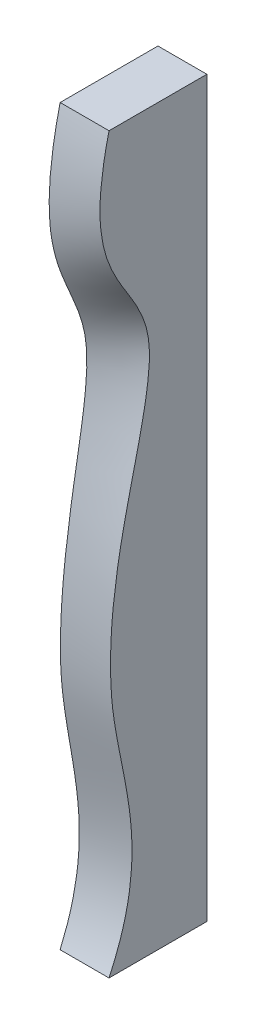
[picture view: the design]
ISO-10303-21;
HEADER;
FILE_DESCRIPTION(('STEP AP214'),'2;1');
FILE_NAME('part.step','',(''),(''),'','','');
FILE_SCHEMA(('AUTOMOTIVE_DESIGN { 1 0 10303 214 1 1 1 1 }'));
ENDSEC;
DATA;
#1=APPLICATION_CONTEXT('core data for automotive mechanical design processes');
#2=APPLICATION_PROTOCOL_DEFINITION('international standard','automotive_design',2000,#1);
#3=PRODUCT_CONTEXT('',#1,'mechanical');
#4=PRODUCT('Part','Part','',(#3));
#5=PRODUCT_RELATED_PRODUCT_CATEGORY('part','',(#4));
#6=PRODUCT_DEFINITION_FORMATION('','',#4);
#7=PRODUCT_DEFINITION_CONTEXT('part definition',#1,'design');
#8=PRODUCT_DEFINITION('design','',#6,#7);
#9=PRODUCT_DEFINITION_SHAPE('','',#8);
#10=(LENGTH_UNIT() NAMED_UNIT(*) SI_UNIT(.MILLI.,.METRE.));
#11=(NAMED_UNIT(*) PLANE_ANGLE_UNIT() SI_UNIT($,.RADIAN.));
#12=(NAMED_UNIT(*) SI_UNIT($,.STERADIAN.) SOLID_ANGLE_UNIT());
#13=UNCERTAINTY_MEASURE_WITH_UNIT(LENGTH_MEASURE(1.E-05),#10,'distance_accuracy_value','');
#14=(GEOMETRIC_REPRESENTATION_CONTEXT(3) GLOBAL_UNCERTAINTY_ASSIGNED_CONTEXT((#13)) GLOBAL_UNIT_ASSIGNED_CONTEXT((#10,
#11,#12)) REPRESENTATION_CONTEXT('',''));
#15=CARTESIAN_POINT('',(0.,0.,0.));
#16=DIRECTION('',(0.,0.,1.));
#17=DIRECTION('',(1.,0.,0.));
#18=AXIS2_PLACEMENT_3D('',#15,#16,#17);
#19=CARTESIAN_POINT('',(-450.,375.,253.120113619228));
#20=DIRECTION('',(1.,0.,0.));
#21=DIRECTION('',(0.,0.,-1.));
#22=AXIS2_PLACEMENT_3D('',#19,#20,#21);
#23=PLANE('',#22);
#24=CARTESIAN_POINT('',(-450.,375.,100.));
#25=CARTESIAN_POINT('',(-450.,373.054078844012,100.473043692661));
#26=CARTESIAN_POINT('',(-450.,371.105040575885,100.933403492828));
#27=CARTESIAN_POINT('',(-450.,367.195140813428,101.827829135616));
#28=CARTESIAN_POINT('',(-450.,365.234261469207,102.261816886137));
#29=CARTESIAN_POINT('',(-450.,361.302031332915,103.100738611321));
#30=CARTESIAN_POINT('',(-450.,359.330667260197,103.5056104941));
#31=CARTESIAN_POINT('',(-450.,355.378793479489,104.283294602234));
#32=CARTESIAN_POINT('',(-450.,353.398274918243,104.656061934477));
#33=CARTESIAN_POINT('',(-450.,349.429373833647,105.366340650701));
#34=CARTESIAN_POINT('',(-450.,347.440986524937,105.703825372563));
#35=CARTESIAN_POINT('',(-450.,343.457586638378,106.340103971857));
#36=CARTESIAN_POINT('',(-450.,341.462572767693,106.638889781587));
#37=CARTESIAN_POINT('',(-450.,337.39918009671,107.203517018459));
#38=CARTESIAN_POINT('',(-450.,335.330598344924,107.467905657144));
#39=CARTESIAN_POINT('',(-450.,331.188662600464,107.94697436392));
#40=CARTESIAN_POINT('',(-450.,329.115311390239,108.161678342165));
#41=CARTESIAN_POINT('',(-450.,324.964980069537,108.536593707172));
#42=CARTESIAN_POINT('',(-450.,322.888003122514,108.696839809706));
#43=CARTESIAN_POINT('',(-450.,318.731540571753,108.957694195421));
#44=CARTESIAN_POINT('',(-450.,316.652057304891,109.058339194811));
#45=CARTESIAN_POINT('',(-450.,312.491685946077,109.19443814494));
#46=CARTESIAN_POINT('',(-450.,310.410798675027,109.229916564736));
#47=CARTESIAN_POINT('',(-450.,306.248660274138,109.229716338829));
#48=CARTESIAN_POINT('',(-450.,304.167409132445,109.194028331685));
#49=CARTESIAN_POINT('',(-450.,300.380221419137,109.05856237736));
#50=CARTESIAN_POINT('',(-450.,298.67383206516,108.971408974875));
#51=CARTESIAN_POINT('',(-450.,295.264415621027,108.741456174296));
#52=CARTESIAN_POINT('',(-450.,293.561389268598,108.598645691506));
#53=CARTESIAN_POINT('',(-450.,290.161400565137,108.254060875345));
#54=CARTESIAN_POINT('',(-450.,288.464437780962,108.052290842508));
#55=CARTESIAN_POINT('',(-450.,285.07923071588,107.586768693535));
#56=CARTESIAN_POINT('',(-450.,283.390985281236,107.323025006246));
#57=CARTESIAN_POINT('',(-450.,280.02582283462,106.730977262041));
#58=CARTESIAN_POINT('',(-450.,278.348905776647,106.402673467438));
#59=CARTESIAN_POINT('',(-450.,275.036439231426,105.685498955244));
#60=CARTESIAN_POINT('',(-450.,273.400659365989,105.297693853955));
#61=CARTESIAN_POINT('',(-450.,270.145564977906,104.456832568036));
#62=CARTESIAN_POINT('',(-450.,268.526254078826,104.00376234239));
#63=CARTESIAN_POINT('',(-450.,265.307226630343,103.032647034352));
#64=CARTESIAN_POINT('',(-450.,263.707510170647,102.51460165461));
#65=CARTESIAN_POINT('',(-450.,260.53038250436,101.415125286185));
#66=CARTESIAN_POINT('',(-450.,258.952966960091,100.833706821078));
#67=CARTESIAN_POINT('',(-450.,255.822675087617,99.6105607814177));
#68=CARTESIAN_POINT('',(-450.,254.269786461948,98.9688646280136));
#69=CARTESIAN_POINT('',(-450.,251.20894457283,97.6379970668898));
#70=CARTESIAN_POINT('',(-450.,249.700668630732,96.9495659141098));
#71=CARTESIAN_POINT('',(-450.,246.707866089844,95.5232025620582));
#72=CARTESIAN_POINT('',(-450.,245.223338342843,94.7852727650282));
#73=CARTESIAN_POINT('',(-450.,242.276082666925,93.2660843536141));
#74=CARTESIAN_POINT('',(-450.,240.813362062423,92.4848115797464));
#75=CARTESIAN_POINT('',(-450.,237.907117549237,90.8863178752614));
#76=CARTESIAN_POINT('',(-450.,236.463600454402,90.0690846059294));
#77=CARTESIAN_POINT('',(-450.,233.592540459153,88.4071985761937));
#78=CARTESIAN_POINT('',(-450.,232.164997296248,87.5625462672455));
#79=CARTESIAN_POINT('',(-450.,229.304642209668,85.8448899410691));
#80=CARTESIAN_POINT('',(-450.,227.871959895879,84.9716711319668));
#81=CARTESIAN_POINT('',(-450.,225.01275188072,83.2165276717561));
#82=CARTESIAN_POINT('',(-450.,223.586223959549,82.3346066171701));
#83=CARTESIAN_POINT('',(-450.,220.732703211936,80.5723377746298));
#84=CARTESIAN_POINT('',(-450.,219.305710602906,79.6919896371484));
#85=CARTESIAN_POINT('',(-450.,216.444365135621,77.9436004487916));
#86=CARTESIAN_POINT('',(-450.,215.010013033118,77.0755581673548));
#87=CARTESIAN_POINT('',(-450.,212.126872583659,75.3627588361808));
#88=CARTESIAN_POINT('',(-450.,210.678080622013,74.518007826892));
#89=CARTESIAN_POINT('',(-450.,208.162277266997,73.0914585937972));
#90=CARTESIAN_POINT('',(-450.,207.100009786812,72.5013146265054));
#91=CARTESIAN_POINT('',(-450.,204.962847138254,71.3437996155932));
#92=CARTESIAN_POINT('',(-450.,203.887949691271,70.7764327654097));
#93=CARTESIAN_POINT('',(-450.,201.724267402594,69.669023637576));
#94=CARTESIAN_POINT('',(-450.,200.635483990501,69.1289785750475));
#95=CARTESIAN_POINT('',(-450.,198.442937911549,68.0804283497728));
#96=CARTESIAN_POINT('',(-450.,197.339176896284,67.5719197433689));
#97=CARTESIAN_POINT('',(-450.,195.115791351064,66.5902446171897));
#98=CARTESIAN_POINT('',(-450.,193.996164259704,66.1170838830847));
#99=CARTESIAN_POINT('',(-450.,191.752941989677,65.214473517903));
#100=CARTESIAN_POINT('',(-450.,190.629509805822,64.7846196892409));
#101=CARTESIAN_POINT('',(-450.,188.367396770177,63.9658926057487));
#102=CARTESIAN_POINT('',(-450.,187.228711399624,63.5770318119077));
#103=CARTESIAN_POINT('',(-450.,184.93741832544,62.842776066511));
#104=CARTESIAN_POINT('',(-450.,183.784810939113,62.497380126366));
#105=CARTESIAN_POINT('',(-450.,181.467248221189,61.8517541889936));
#106=CARTESIAN_POINT('',(-450.,180.302295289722,61.5515155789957));
#107=CARTESIAN_POINT('',(-450.,177.961801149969,60.9971418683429));
#108=CARTESIAN_POINT('',(-450.,176.78626312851,60.7429933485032));
#109=CARTESIAN_POINT('',(-450.,174.865937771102,60.3670259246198));
#110=CARTESIAN_POINT('',(-450.,174.123863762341,60.2311859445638));
#111=CARTESIAN_POINT('',(-450.,172.636608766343,59.9776144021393));
#112=CARTESIAN_POINT('',(-450.,171.891427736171,59.8598830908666));
#113=CARTESIAN_POINT('',(-450.,170.398333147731,59.6423569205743));
#114=CARTESIAN_POINT('',(-450.,169.650419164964,59.5425649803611));
#115=CARTESIAN_POINT('',(-450.,168.152447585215,59.3606954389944));
#116=CARTESIAN_POINT('',(-450.,167.402389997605,59.2786177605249));
#117=CARTESIAN_POINT('',(-450.,165.900393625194,59.1318419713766));
#118=CARTESIAN_POINT('',(-450.,165.148454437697,59.0671479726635));
#119=CARTESIAN_POINT('',(-450.,164.019608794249,58.9828775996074));
#120=CARTESIAN_POINT('',(-450.,163.643168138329,58.956915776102));
#121=CARTESIAN_POINT('',(-450.,162.890020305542,58.9091950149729));
#122=CARTESIAN_POINT('',(-450.,162.513313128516,58.8874360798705));
#123=CARTESIAN_POINT('',(-450.,161.382934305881,58.8282291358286));
#124=CARTESIAN_POINT('',(-450.,160.628937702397,58.7968459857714));
#125=CARTESIAN_POINT('',(-450.,159.120486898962,58.7490790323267));
#126=CARTESIAN_POINT('',(-450.,158.366032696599,58.7326953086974));
#127=CARTESIAN_POINT('',(-450.,156.088166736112,58.7042043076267));
#128=CARTESIAN_POINT('',(-450.,154.564456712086,58.7134607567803));
#129=CARTESIAN_POINT('',(-450.,151.518475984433,58.7805954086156));
#130=CARTESIAN_POINT('',(-450.,149.996205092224,58.8384659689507));
#131=CARTESIAN_POINT('',(-450.,146.953719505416,58.996064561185));
#132=CARTESIAN_POINT('',(-450.,145.433505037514,59.0957968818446));
#133=CARTESIAN_POINT('',(-450.,142.395883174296,59.3313312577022));
#134=CARTESIAN_POINT('',(-450.,140.878475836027,59.4671340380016));
#135=CARTESIAN_POINT('',(-450.,138.222922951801,59.7322892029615));
#136=CARTESIAN_POINT('',(-450.,137.08409199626,59.8548815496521));
#137=CARTESIAN_POINT('',(-450.,134.808233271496,60.1158083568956));
#138=CARTESIAN_POINT('',(-450.,133.671205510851,60.2541428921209));
#139=CARTESIAN_POINT('',(-450.,131.399025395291,60.5448327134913));
#140=CARTESIAN_POINT('',(-450.,130.263872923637,60.6971870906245));
#141=CARTESIAN_POINT('',(-450.,127.995353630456,61.014575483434));
#142=CARTESIAN_POINT('',(-450.,126.861986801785,61.1796094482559));
#143=CARTESIAN_POINT('',(-450.,123.463966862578,61.6921072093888));
#144=CARTESIAN_POINT('',(-450.,121.201916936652,62.0568989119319));
#145=CARTESIAN_POINT('',(-450.,116.6837291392,62.8247444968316));
#146=CARTESIAN_POINT('',(-450.,114.42759311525,63.2278091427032));
#147=CARTESIAN_POINT('',(-450.,109.920836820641,64.0654565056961));
#148=CARTESIAN_POINT('',(-450.,107.670217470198,64.5000441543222));
#149=CARTESIAN_POINT('',(-450.,103.174286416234,65.3948633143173));
#150=CARTESIAN_POINT('',(-450.,100.928974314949,65.8550928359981));
#151=CARTESIAN_POINT('',(-450.,96.4483015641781,66.7950387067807));
#152=CARTESIAN_POINT('',(-450.,94.2129300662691,67.2747035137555));
#153=CARTESIAN_POINT('',(-450.,89.7463804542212,68.2500712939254));
#154=CARTESIAN_POINT('',(-450.,87.5152013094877,68.7457695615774));
#155=CARTESIAN_POINT('',(-450.,83.0560024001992,69.7493467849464));
#156=CARTESIAN_POINT('',(-450.,80.8279821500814,70.2572235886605));
#157=CARTESIAN_POINT('',(-450.,76.3741532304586,71.2816720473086));
#158=CARTESIAN_POINT('',(-450.,74.148344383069,71.7982429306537));
#159=CARTESIAN_POINT('',(-450.,69.6980585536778,72.8368886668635));
#160=CARTESIAN_POINT('',(-450.,67.4735815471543,73.3589634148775));
#161=CARTESIAN_POINT('',(-450.,63.0251338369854,74.4056608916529));
#162=CARTESIAN_POINT('',(-450.,60.8011631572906,74.9302837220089));
#163=CARTESIAN_POINT('',(-450.,56.362089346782,75.9771531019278));
#164=CARTESIAN_POINT('',(-450.,54.1469864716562,76.4994007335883));
#165=CARTESIAN_POINT('',(-450.,49.7160051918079,77.5410378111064));
#166=CARTESIAN_POINT('',(-450.,47.5001267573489,78.0604271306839));
#167=CARTESIAN_POINT('',(-450.,43.0671209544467,79.0938320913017));
#168=CARTESIAN_POINT('',(-450.,40.849993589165,79.6078477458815));
#169=CARTESIAN_POINT('',(-450.,36.4123869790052,80.6284787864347));
#170=CARTESIAN_POINT('',(-450.,34.191906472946,81.1350886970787));
#171=CARTESIAN_POINT('',(-450.,29.7486587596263,82.1382383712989));
#172=CARTESIAN_POINT('',(-450.,27.5258915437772,82.6347780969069));
#173=CARTESIAN_POINT('',(-450.,23.0775097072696,83.6156049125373));
#174=CARTESIAN_POINT('',(-450.,20.8518949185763,84.099891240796));
#175=CARTESIAN_POINT('',(-450.,15.2742197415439,85.2946888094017));
#176=CARTESIAN_POINT('',(-450.,11.9202002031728,85.9961006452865));
#177=CARTESIAN_POINT('',(-450.,5.20393184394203,87.3589272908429));
#178=CARTESIAN_POINT('',(-450.,1.84168282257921,88.0203411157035));
#179=CARTESIAN_POINT('',(-450.,-4.8914812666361,89.2960689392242));
#180=CARTESIAN_POINT('',(-450.,-8.26239559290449,89.9103868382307));
#181=CARTESIAN_POINT('',(-450.,-15.0130809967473,91.0860798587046));
#182=CARTESIAN_POINT('',(-450.,-18.3928510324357,91.6474609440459));
#183=CARTESIAN_POINT('',(-450.,-25.1552878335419,92.7111783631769));
#184=CARTESIAN_POINT('',(-450.,-28.5379376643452,93.2136220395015));
#185=CARTESIAN_POINT('',(-450.,-35.3121317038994,94.1563057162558));
#186=CARTESIAN_POINT('',(-450.,-38.703676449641,94.5965418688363));
#187=CARTESIAN_POINT('',(-450.,-45.4953812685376,95.41119991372));
#188=CARTESIAN_POINT('',(-450.,-48.8955429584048,95.7856083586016));
#189=CARTESIAN_POINT('',(-450.,-55.7041557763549,96.4655589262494));
#190=CARTESIAN_POINT('',(-450.,-59.11260968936,96.7710732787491));
#191=CARTESIAN_POINT('',(-450.,-65.3963663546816,97.2676476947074));
#192=CARTESIAN_POINT('',(-450.,-68.2708455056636,97.4691637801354));
#193=CARTESIAN_POINT('',(-450.,-74.0234322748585,97.819522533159));
#194=CARTESIAN_POINT('',(-450.,-76.9015403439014,97.968357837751));
#195=CARTESIAN_POINT('',(-450.,-82.6598216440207,98.2113179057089));
#196=CARTESIAN_POINT('',(-450.,-85.5399946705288,98.3054474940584));
#197=CARTESIAN_POINT('',(-450.,-91.3008667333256,98.4365930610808));
#198=CARTESIAN_POINT('',(-450.,-94.1815654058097,98.4736247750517));
#199=CARTESIAN_POINT('',(-450.,-99.9419461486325,98.4876499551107));
#200=CARTESIAN_POINT('',(-450.,-102.821628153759,98.4646679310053));
#201=CARTESIAN_POINT('',(-450.,-108.578504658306,98.355103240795));
#202=CARTESIAN_POINT('',(-450.,-111.455699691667,98.2685501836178));
#203=CARTESIAN_POINT('',(-450.,-115.777404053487,98.0874016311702));
#204=CARTESIAN_POINT('',(-450.,-117.223010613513,98.0181993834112));
#205=CARTESIAN_POINT('',(-450.,-120.113267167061,97.8619642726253));
#206=CARTESIAN_POINT('',(-450.,-121.557917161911,97.7749314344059));
#207=CARTESIAN_POINT('',(-450.,-124.446008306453,97.5823509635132));
#208=CARTESIAN_POINT('',(-450.,-125.889449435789,97.4768030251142));
#209=CARTESIAN_POINT('',(-450.,-128.774803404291,97.2464537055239));
#210=CARTESIAN_POINT('',(-450.,-130.216716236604,97.1216522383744));
#211=CARTESIAN_POINT('',(-450.,-133.098789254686,96.8519971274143));
#212=CARTESIAN_POINT('',(-450.,-134.538949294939,96.7071419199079));
#213=CARTESIAN_POINT('',(-450.,-136.697480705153,96.474190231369));
#214=CARTESIAN_POINT('',(-450.,-137.416704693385,96.3939283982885));
#215=CARTESIAN_POINT('',(-450.,-138.854539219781,96.22807927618));
#216=CARTESIAN_POINT('',(-450.,-139.573149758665,96.1424919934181));
#217=CARTESIAN_POINT('',(-450.,-141.009906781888,95.9658169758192));
#218=CARTESIAN_POINT('',(-450.,-141.728053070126,95.8747276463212));
#219=CARTESIAN_POINT('',(-450.,-143.163634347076,95.6871074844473));
#220=CARTESIAN_POINT('',(-450.,-143.881069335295,95.5905766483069));
#221=CARTESIAN_POINT('',(-450.,-145.315259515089,95.3925531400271));
#222=CARTESIAN_POINT('',(-450.,-146.032014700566,95.2910604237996));
#223=CARTESIAN_POINT('',(-450.,-147.464865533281,95.0835263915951));
#224=CARTESIAN_POINT('',(-450.,-148.1809611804,94.977485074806));
#225=CARTESIAN_POINT('',(-450.,-149.612728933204,94.761260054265));
#226=CARTESIAN_POINT('',(-450.,-150.328400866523,94.6510752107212));
#227=CARTESIAN_POINT('',(-450.,-151.759166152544,94.4270152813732));
#228=CARTESIAN_POINT('',(-450.,-152.474259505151,94.3131401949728));
#229=CARTESIAN_POINT('',(-450.,-153.903921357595,94.0821558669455));
#230=CARTESIAN_POINT('',(-450.,-154.618489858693,93.9650466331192));
#231=CARTESIAN_POINT('',(-450.,-156.047141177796,93.7279065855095));
#232=CARTESIAN_POINT('',(-450.,-156.761223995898,93.6078757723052));
#233=CARTESIAN_POINT('',(-450.,-158.90248430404,93.2437125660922));
#234=CARTESIAN_POINT('',(-450.,-160.328962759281,92.9954625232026));
#235=CARTESIAN_POINT('',(-450.,-163.180242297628,92.4895544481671));
#236=CARTESIAN_POINT('',(-450.,-164.605043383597,92.2318964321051));
#237=CARTESIAN_POINT('',(-450.,-167.633419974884,91.6755989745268));
#238=CARTESIAN_POINT('',(-450.,-169.236800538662,91.3758998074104));
#239=CARTESIAN_POINT('',(-450.,-172.442079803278,90.7686842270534));
#240=CARTESIAN_POINT('',(-450.,-174.043978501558,90.461167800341));
#241=CARTESIAN_POINT('',(-450.,-178.846902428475,89.5303498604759));
#242=CARTESIAN_POINT('',(-450.,-182.046278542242,88.8985702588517));
#243=CARTESIAN_POINT('',(-450.,-188.443552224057,87.6295600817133));
#244=CARTESIAN_POINT('',(-450.,-191.641449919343,86.9923301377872));
#245=CARTESIAN_POINT('',(-450.,-198.039812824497,85.7292422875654));
#246=CARTESIAN_POINT('',(-450.,-201.240278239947,85.1033854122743));
#247=CARTESIAN_POINT('',(-450.,-207.647796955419,83.8797922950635));
#248=CARTESIAN_POINT('',(-450.,-210.854852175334,83.2820660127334));
#249=CARTESIAN_POINT('',(-450.,-217.279554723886,82.1313937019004));
#250=CARTESIAN_POINT('',(-450.,-220.497208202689,81.5784816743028));
#251=CARTESIAN_POINT('',(-450.,-226.908562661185,80.5401919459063));
#252=CARTESIAN_POINT('',(-450.,-230.102156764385,80.0541614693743));
#253=CARTESIAN_POINT('',(-450.,-236.501608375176,79.1584421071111));
#254=CARTESIAN_POINT('',(-450.,-239.707470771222,78.7487878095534));
#255=CARTESIAN_POINT('',(-450.,-246.12886662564,78.0213891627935));
#256=CARTESIAN_POINT('',(-450.,-249.344396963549,77.7036178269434));
#257=CARTESIAN_POINT('',(-450.,-254.173147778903,77.3063812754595));
#258=CARTESIAN_POINT('',(-450.,-255.78315731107,77.1872296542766));
#259=CARTESIAN_POINT('',(-450.,-259.004993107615,76.9769255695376));
#260=CARTESIAN_POINT('',(-450.,-260.616819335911,76.8857725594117));
#261=CARTESIAN_POINT('',(-450.,-263.840940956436,76.7330059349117));
#262=CARTESIAN_POINT('',(-450.,-265.453235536,76.6713752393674));
#263=CARTESIAN_POINT('',(-450.,-268.678680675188,76.5789302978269));
#264=CARTESIAN_POINT('',(-450.,-270.291831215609,76.5481153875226));
#265=CARTESIAN_POINT('',(-450.,-273.518123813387,76.5185143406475));
#266=CARTESIAN_POINT('',(-450.,-275.131265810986,76.5197219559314));
#267=CARTESIAN_POINT('',(-450.,-278.357159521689,76.5551911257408));
#268=CARTESIAN_POINT('',(-450.,-279.969911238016,76.5894523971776));
#269=CARTESIAN_POINT('',(-450.,-284.262125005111,76.7258630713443));
#270=CARTESIAN_POINT('',(-450.,-286.94070605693,76.8579451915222));
#271=CARTESIAN_POINT('',(-450.,-292.29223295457,77.2189356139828));
#272=CARTESIAN_POINT('',(-450.,-294.965176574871,77.4478768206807));
#273=CARTESIAN_POINT('',(-450.,-300.301296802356,78.004117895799));
#274=CARTESIAN_POINT('',(-450.,-302.964471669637,78.3314344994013));
#275=CARTESIAN_POINT('',(-450.,-308.27702386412,79.0845248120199));
#276=CARTESIAN_POINT('',(-450.,-310.926400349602,79.5103044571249));
#277=CARTESIAN_POINT('',(-450.,-316.207513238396,80.4590695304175));
#278=CARTESIAN_POINT('',(-450.,-318.839250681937,80.9820491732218));
#279=CARTESIAN_POINT('',(-450.,-324.095208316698,82.1257496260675));
#280=CARTESIAN_POINT('',(-450.,-326.719324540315,82.7469476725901));
#281=CARTESIAN_POINT('',(-450.,-331.9438344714,84.081840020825));
#282=CARTESIAN_POINT('',(-450.,-334.544228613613,84.7955326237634));
#283=CARTESIAN_POINT('',(-450.,-339.718999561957,86.3113637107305));
#284=CARTESIAN_POINT('',(-450.,-342.293377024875,87.1134999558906));
#285=CARTESIAN_POINT('',(-450.,-347.413989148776,88.8015544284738));
#286=CARTESIAN_POINT('',(-450.,-349.960228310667,89.687459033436));
#287=CARTESIAN_POINT('',(-450.,-355.022673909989,91.5379550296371));
#288=CARTESIAN_POINT('',(-450.,-357.538893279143,92.5025110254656));
#289=CARTESIAN_POINT('',(-450.,-360.883259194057,93.8416636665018));
#290=CARTESIAN_POINT('',(-450.,-361.724662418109,94.1834631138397));
#291=CARTESIAN_POINT('',(-450.,-363.403928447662,94.8752289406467));
#292=CARTESIAN_POINT('',(-450.,-364.241791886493,95.2251937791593));
#293=CARTESIAN_POINT('',(-450.,-365.914037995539,95.9331299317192));
#294=CARTESIAN_POINT('',(-450.,-366.748420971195,96.2911005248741));
#295=CARTESIAN_POINT('',(-450.,-368.410410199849,97.0134314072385));
#296=CARTESIAN_POINT('',(-450.,-369.23803021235,97.3777600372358));
#297=CARTESIAN_POINT('',(-450.,-370.889951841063,98.1140560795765));
#298=CARTESIAN_POINT('',(-450.,-371.71425315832,98.4860241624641));
#299=CARTESIAN_POINT('',(-450.,-373.359602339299,99.2374520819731));
#300=CARTESIAN_POINT('',(-450.,-374.180649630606,99.616913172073));
#301=CARTESIAN_POINT('',(-450.,-375.,100.));
#302=B_SPLINE_CURVE_WITH_KNOTS('',3,(#24,#25,#26,#27,#28,#29,#30,#31,#32,#33,#34,#35,#36,#37,
#38,#39,#40,#41,#42,#43,#44,#45,#46,#47,#48,#49,#50,#51,#52,#53,#54,#55,#56,#57,#58,#59,#60,#61,
#62,#63,#64,#65,#66,#67,#68,#69,#70,#71,#72,#73,#74,#75,#76,#77,#78,#79,#80,#81,#82,#83,#84,#85,
#86,#87,#88,#89,#90,#91,#92,#93,#94,#95,#96,#97,#98,#99,#100,#101,#102,#103,#104,#105,#106,#107,
#108,#109,#110,#111,#112,#113,#114,#115,#116,#117,#118,#119,#120,#121,#122,#123,#124,#125,#126,
#127,#128,#129,#130,#131,#132,#133,#134,#135,#136,#137,#138,#139,#140,#141,#142,#143,#144,#145,
#146,#147,#148,#149,#150,#151,#152,#153,#154,#155,#156,#157,#158,#159,#160,#161,#162,#163,#164,
#165,#166,#167,#168,#169,#170,#171,#172,#173,#174,#175,#176,#177,#178,#179,#180,#181,#182,#183,
#184,#185,#186,#187,#188,#189,#190,#191,#192,#193,#194,#195,#196,#197,#198,#199,#200,#201,#202,
#203,#204,#205,#206,#207,#208,#209,#210,#211,#212,#213,#214,#215,#216,#217,#218,#219,#220,#221,
#222,#223,#224,#225,#226,#227,#228,#229,#230,#231,#232,#233,#234,#235,#236,#237,#238,#239,#240,
#241,#242,#243,#244,#245,#246,#247,#248,#249,#250,#251,#252,#253,#254,#255,#256,#257,#258,#259,
#260,#261,#262,#263,#264,#265,#266,#267,#268,#269,#270,#271,#272,#273,#274,#275,#276,#277,#278,
#279,#280,#281,#282,#283,#284,#285,#286,#287,#288,#289,#290,#291,#292,#293,#294,#295,#296,#297,
#298,#299,#300,#301),.UNSPECIFIED.,.F.,.F.,(4,2,2,2,2,2,2,2,2,2,2,2,2,2,2,2,2,2,2,2,2,2,2,2,2,2,
2,2,2,2,2,2,2,2,2,2,2,2,2,2,2,2,2,2,2,2,2,2,2,2,2,2,2,2,2,2,2,2,2,2,2,2,2,2,2,2,2,2,2,2,2,2,2,2,
2,2,2,2,2,2,2,2,2,2,2,2,2,2,2,2,2,2,2,2,2,2,2,2,2,2,2,2,2,2,2,2,2,2,2,2,2,2,2,2,2,2,2,2,2,2,2,2,
2,2,2,2,2,2,2,2,2,2,2,2,2,2,2,2,4),(0.,6.00778556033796,12.0325717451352,18.069847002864,
24.11543181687,30.1655525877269,36.2169326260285,42.4726128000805,48.7252762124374,
54.9739461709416,61.2187627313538,67.4612339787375,73.7045264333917,78.8295413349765,
83.9555774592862,89.0812397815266,94.2062053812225,99.3311501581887,104.373195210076,
109.416326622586,114.459481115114,119.501640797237,124.541186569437,129.514071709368,
134.486715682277,139.460993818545,144.436992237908,149.412908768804,154.446301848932,
159.477695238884,164.507780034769,169.537358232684,174.568228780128,178.213568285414,
181.85957587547,185.505211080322,189.150447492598,192.79627924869,196.404110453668,
200.013035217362,203.621877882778,207.230031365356,210.837132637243,213.100145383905,
215.363189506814,217.626601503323,219.890003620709,222.153940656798,223.285924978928,
224.417909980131,226.681676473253,228.945455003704,233.515651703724,238.08513008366,
242.655076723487,247.225115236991,250.661234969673,254.097371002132,257.533284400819,
260.969184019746,267.842564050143,274.717882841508,281.594279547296,288.4701434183,
295.328833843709,302.1855293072,309.04102196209,315.895909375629,322.750666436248,
329.605699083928,336.433202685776,343.261005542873,350.088791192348,356.921392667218,
363.754019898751,370.587070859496,380.866593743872,391.146369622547,401.425293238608,
411.70305744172,421.961802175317,432.221181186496,442.482653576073,452.74825486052,
461.392403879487,470.03776058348,478.682354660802,487.32456599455,495.963248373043,
504.597909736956,508.939605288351,513.281294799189,517.623056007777,521.964836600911,
526.306955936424,528.478005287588,530.649052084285,532.820731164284,534.992411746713,
537.164111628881,539.335811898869,541.508113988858,543.680416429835,545.852713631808,
548.025010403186,552.368725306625,556.712432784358,561.605855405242,566.499286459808,
576.282721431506,586.065037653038,595.848236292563,605.634872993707,615.428866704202,
625.119213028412,634.813937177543,644.505811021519,649.348846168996,654.191786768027,
659.031921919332,663.871952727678,668.711039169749,673.550084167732,681.593774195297,
689.640198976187,697.687993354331,705.736273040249,713.784073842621,721.87225329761,
729.960284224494,738.048110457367,746.134623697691,754.217517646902,756.94202386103,
759.666020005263,762.38977184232,765.102519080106,767.815505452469,770.528949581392),.UNSPECIFIED.);
#303=CARTESIAN_POINT('',(-450.,375.,100.));
#304=VERTEX_POINT('',#303);
#305=CARTESIAN_POINT('',(-450.,-375.,100.));
#306=VERTEX_POINT('',#305);
#307=EDGE_CURVE('E88',#304,#306,#302,.T.);
#308=ORIENTED_EDGE('',*,*,#307,.T.);
#309=DIRECTION('',(0.,0.,-1.));
#310=VECTOR('',#309,1.);
#311=CARTESIAN_POINT('',(-450.,-375.,253.120113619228));
#312=LINE('',#311,#310);
#313=CARTESIAN_POINT('',(-450.,-375.,0.));
#314=VERTEX_POINT('',#313);
#315=EDGE_CURVE('E50',#306,#314,#312,.T.);
#316=ORIENTED_EDGE('',*,*,#315,.T.);
#317=DIRECTION('',(0.,-1.,0.));
#318=VECTOR('',#317,1.);
#319=CARTESIAN_POINT('',(-450.,375.,0.));
#320=LINE('',#319,#318);
#321=CARTESIAN_POINT('',(-450.,375.,0.));
#322=VERTEX_POINT('',#321);
#323=EDGE_CURVE('E87',#322,#314,#320,.T.);
#324=ORIENTED_EDGE('',*,*,#323,.F.);
#325=DIRECTION('',(0.,0.,-1.));
#326=VECTOR('',#325,1.);
#327=CARTESIAN_POINT('',(-450.,375.,253.120113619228));
#328=LINE('',#327,#326);
#329=EDGE_CURVE('E65',#304,#322,#328,.T.);
#330=ORIENTED_EDGE('',*,*,#329,.F.);
#331=EDGE_LOOP('',(#308,#316,#324,#330));
#332=FACE_BOUND('',#331,.T.);
#333=ADVANCED_FACE('F35',(#332),#23,.T.);
#334=CARTESIAN_POINT('',(0.,0.,0.));
#335=DIRECTION('',(0.,0.,-1.));
#336=DIRECTION('',(-1.,0.,0.));
#337=AXIS2_PLACEMENT_3D('',#334,#335,#336);
#338=PLANE('',#337);
#339=DIRECTION('',(1.,0.,0.));
#340=VECTOR('',#339,1.);
#341=CARTESIAN_POINT('',(-750.,-375.,0.));
#342=LINE('',#341,#340);
#343=CARTESIAN_POINT('',(-500.,-375.,0.));
#344=VERTEX_POINT('',#343);
#345=EDGE_CURVE('E79',#344,#314,#342,.T.);
#346=ORIENTED_EDGE('',*,*,#345,.F.);
#347=DIRECTION('',(0.,1.,0.));
#348=VECTOR('',#347,1.);
#349=CARTESIAN_POINT('',(-500.,375.,0.));
#350=LINE('',#349,#348);
#351=CARTESIAN_POINT('',(-500.,375.,0.));
#352=VERTEX_POINT('',#351);
#353=EDGE_CURVE('E157',#344,#352,#350,.T.);
#354=ORIENTED_EDGE('',*,*,#353,.T.);
#355=DIRECTION('',(-1.,0.,0.));
#356=VECTOR('',#355,1.);
#357=CARTESIAN_POINT('',(-750.,375.,0.));
#358=LINE('',#357,#356);
#359=EDGE_CURVE('E93',#322,#352,#358,.T.);
#360=ORIENTED_EDGE('',*,*,#359,.F.);
#361=ORIENTED_EDGE('',*,*,#323,.T.);
#362=EDGE_LOOP('',(#346,#354,#360,#361));
#363=FACE_BOUND('',#362,.T.);
#364=ADVANCED_FACE('F91',(#363),#338,.T.);
#365=CARTESIAN_POINT('',(750.,-375.,100.));
#366=CARTESIAN_POINT('',(750.,-302.078506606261,100.));
#367=CARTESIAN_POINT('',(750.,-224.483786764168,100.));
#368=CARTESIAN_POINT('',(750.,-61.5160152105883,100.));
#369=CARTESIAN_POINT('',(750.,39.4445673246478,100.));
#370=CARTESIAN_POINT('',(750.,211.849847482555,100.));
#371=CARTESIAN_POINT('',(750.,298.882075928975,100.));
#372=CARTESIAN_POINT('',(750.,375.,100.));
#373=CARTESIAN_POINT('',(669.085175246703,-375.,100.));
#374=CARTESIAN_POINT('',(669.085175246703,-302.078506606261,100.));
#375=CARTESIAN_POINT('',(669.085175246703,-234.282472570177,121.198481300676));
#376=CARTESIAN_POINT('',(669.085175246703,-62.2283080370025,120.288550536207));
#377=CARTESIAN_POINT('',(669.085175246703,68.0647781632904,82.7868169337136));
#378=CARTESIAN_POINT('',(669.085175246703,240.312514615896,73.0426687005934));
#379=CARTESIAN_POINT('',(669.085175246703,298.882075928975,100.));
#380=CARTESIAN_POINT('',(669.085175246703,375.,100.));
#381=CARTESIAN_POINT('',(500.445116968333,-375.,100.));
#382=CARTESIAN_POINT('',(517.991528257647,-284.627602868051,95.5040591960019));
#383=CARTESIAN_POINT('',(530.038001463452,-221.673003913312,150.719602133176));
#384=CARTESIAN_POINT('',(473.74510655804,-71.7416270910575,167.060530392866));
#385=CARTESIAN_POINT('',(387.213321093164,45.6135081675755,91.591323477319));
#386=CARTESIAN_POINT('',(378.694107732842,207.638743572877,66.6461848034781));
#387=CARTESIAN_POINT('',(433.17831170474,253.396603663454,122.492891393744));
#388=CARTESIAN_POINT('',(500.445116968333,375.,100.));
#389=CARTESIAN_POINT('',(285.091607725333,-375.,100.));
#390=CARTESIAN_POINT('',(309.270321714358,-264.297524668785,86.4064578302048));
#391=CARTESIAN_POINT('',(325.856840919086,-200.08226970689,164.07204721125));
#392=CARTESIAN_POINT('',(247.47112957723,-80.9425320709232,234.992870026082));
#393=CARTESIAN_POINT('',(127.240382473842,2.40271344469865,186.756001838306));
#394=CARTESIAN_POINT('',(115.567806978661,152.518027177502,151.057444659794));
#395=CARTESIAN_POINT('',(191.428893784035,202.025100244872,189.039851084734));
#396=CARTESIAN_POINT('',(285.091607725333,375.,100.));
#397=CARTESIAN_POINT('',(47.4554331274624,-375.,100.));
#398=CARTESIAN_POINT('',(51.0669239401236,-278.639867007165,99.5141662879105));
#399=CARTESIAN_POINT('',(52.9210710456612,-231.452124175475,201.325948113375));
#400=CARTESIAN_POINT('',(3.18149891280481,-90.8615864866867,272.445475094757));
#401=CARTESIAN_POINT('',(-61.0346058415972,45.7948958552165,186.157760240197));
#402=CARTESIAN_POINT('',(-59.6612105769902,205.286893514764,133.941969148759));
#403=CARTESIAN_POINT('',(-11.8049718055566,220.40073671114,189.8209162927));
#404=CARTESIAN_POINT('',(47.4554331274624,375.,100.));
#405=CARTESIAN_POINT('',(-175.903454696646,-375.,100.));
#406=CARTESIAN_POINT('',(-199.823715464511,-320.588060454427,126.731848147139));
#407=CARTESIAN_POINT('',(-216.967937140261,-300.821135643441,242.921959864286));
#408=CARTESIAN_POINT('',(-184.265304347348,-55.1410097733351,206.147478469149));
#409=CARTESIAN_POINT('',(-119.865061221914,249.096629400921,-32.5779079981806));
#410=CARTESIAN_POINT('',(-104.641938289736,431.262460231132,-94.4845569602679));
#411=CARTESIAN_POINT('',(-136.623034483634,348.137040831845,60.785640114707));
#412=CARTESIAN_POINT('',(-175.903454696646,375.,100.));
#413=CARTESIAN_POINT('',(-355.235514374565,-375.,100.));
#414=CARTESIAN_POINT('',(-319.200833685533,-282.590755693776,58.2859511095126));
#415=CARTESIAN_POINT('',(-293.075279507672,-226.888141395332,104.97090627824));
#416=CARTESIAN_POINT('',(-324.119079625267,-68.6572837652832,122.102733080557));
#417=CARTESIAN_POINT('',(-398.972481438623,73.039345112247,53.3701087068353));
#418=CARTESIAN_POINT('',(-423.398679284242,233.384819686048,47.4380317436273));
#419=CARTESIAN_POINT('',(-392.720188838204,253.575952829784,124.952096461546));
#420=CARTESIAN_POINT('',(-355.235514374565,375.,100.));
#421=CARTESIAN_POINT('',(-536.684515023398,-375.,100.));
#422=CARTESIAN_POINT('',(-494.827225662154,-277.129657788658,52.0422385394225));
#423=CARTESIAN_POINT('',(-464.573647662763,-205.017596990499,67.039018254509));
#424=CARTESIAN_POINT('',(-506.334367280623,-72.2467511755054,96.5036749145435));
#425=CARTESIAN_POINT('',(-600.216684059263,9.35641022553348,95.9941925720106));
#426=CARTESIAN_POINT('',(-628.122542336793,166.946160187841,106.349064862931));
#427=CARTESIAN_POINT('',(-587.011939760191,237.095914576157,138.331902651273));
#428=CARTESIAN_POINT('',(-536.684515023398,375.,100.));
#429=CARTESIAN_POINT('',(-644.685568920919,-375.,100.));
#430=CARTESIAN_POINT('',(-644.685568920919,-302.078506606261,100.));
#431=CARTESIAN_POINT('',(-644.685568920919,-237.237234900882,127.59081546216));
#432=CARTESIAN_POINT('',(-644.685568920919,-62.4430976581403,126.406497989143));
#433=CARTESIAN_POINT('',(-644.685568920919,76.6951111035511,77.5962366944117));
#434=CARTESIAN_POINT('',(-644.685568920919,248.895340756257,64.9137717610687));
#435=CARTESIAN_POINT('',(-644.685568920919,298.882075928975,100.));
#436=CARTESIAN_POINT('',(-644.685568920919,375.,100.));
#437=CARTESIAN_POINT('',(-750.,-375.,100.));
#438=CARTESIAN_POINT('',(-750.,-302.078506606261,100.));
#439=CARTESIAN_POINT('',(-750.,-224.483786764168,100.));
#440=CARTESIAN_POINT('',(-750.,-61.5160152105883,100.));
#441=CARTESIAN_POINT('',(-750.,39.4445673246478,100.));
#442=CARTESIAN_POINT('',(-750.,211.849847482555,100.));
#443=CARTESIAN_POINT('',(-750.,298.882075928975,100.));
#444=CARTESIAN_POINT('',(-750.,375.,100.));
#445=B_SPLINE_SURFACE_WITH_KNOTS('',3,3,((#365,#366,#367,#368,#369,#370,#371,#372),(#373,#374,
#375,#376,#377,#378,#379,#380),(#381,#382,#383,#384,#385,#386,#387,#388),(#389,#390,#391,#392,
#393,#394,#395,#396),(#397,#398,#399,#400,#401,#402,#403,#404),(#405,#406,#407,#408,#409,#410,
#411,#412),(#413,#414,#415,#416,#417,#418,#419,#420),(#421,#422,#423,#424,#425,#426,#427,#428),
(#429,#430,#431,#432,#433,#434,#435,#436),(#437,#438,#439,#440,#441,#442,#443,#444)),
.UNSPECIFIED.,.F.,.F.,.F.,(4,1,1,1,1,1,1,4),(4,1,1,1,1,4),(0.,0.161829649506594,
0.33728011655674,0.430707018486,0.637101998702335,0.783997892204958,0.789371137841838,1.),(0.,
0.291685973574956,0.310378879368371,0.65187108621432,0.695528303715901,1.),.UNSPECIFIED.);
#446=CARTESIAN_POINT('',(-500.,-375.,100.));
#447=CARTESIAN_POINT('',(-500.,-372.867702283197,99.078092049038));
#448=CARTESIAN_POINT('',(-500.,-370.723524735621,98.1834728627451));
#449=CARTESIAN_POINT('',(-500.,-366.411204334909,96.4514749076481));
#450=CARTESIAN_POINT('',(-500.,-364.243052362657,95.6141188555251));
#451=CARTESIAN_POINT('',(-500.,-359.883933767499,93.9999210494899));
#452=CARTESIAN_POINT('',(-500.,-357.692963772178,93.2230883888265));
#453=CARTESIAN_POINT('',(-500.,-353.289524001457,91.7329143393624));
#454=CARTESIAN_POINT('',(-500.,-351.077054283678,91.0195727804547));
#455=CARTESIAN_POINT('',(-500.,-346.632028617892,89.6590291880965));
#456=CARTESIAN_POINT('',(-500.,-344.399474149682,89.0118223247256));
#457=CARTESIAN_POINT('',(-500.,-339.91582763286,87.7857985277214));
#458=CARTESIAN_POINT('',(-500.,-337.664737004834,87.2069764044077));
#459=CARTESIAN_POINT('',(-500.,-333.236656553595,86.1413918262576));
#460=CARTESIAN_POINT('',(-500.,-331.060332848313,85.6518609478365));
#461=CARTESIAN_POINT('',(-500.,-326.694256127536,84.7386552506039));
#462=CARTESIAN_POINT('',(-500.,-324.504505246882,84.3149702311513));
#463=CARTESIAN_POINT('',(-500.,-320.113466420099,83.5340620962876));
#464=CARTESIAN_POINT('',(-500.,-317.912179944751,83.1768307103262));
#465=CARTESIAN_POINT('',(-500.,-313.50004294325,82.5288685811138));
#466=CARTESIAN_POINT('',(-500.,-311.289193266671,82.238132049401));
#467=CARTESIAN_POINT('',(-500.,-306.859986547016,81.722607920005));
#468=CARTESIAN_POINT('',(-500.,-304.64163005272,81.4978156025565));
#469=CARTESIAN_POINT('',(-500.,-300.199573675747,81.1130149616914));
#470=CARTESIAN_POINT('',(-500.,-297.975874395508,80.9529996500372));
#471=CARTESIAN_POINT('',(-500.,-293.121432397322,80.672662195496));
#472=CARTESIAN_POINT('',(-500.,-290.489966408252,80.5647915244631));
#473=CARTESIAN_POINT('',(-500.,-285.224512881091,80.4329725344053));
#474=CARTESIAN_POINT('',(-500.,-282.590524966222,80.4090397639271));
#475=CARTESIAN_POINT('',(-500.,-277.322327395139,80.4401186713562));
#476=CARTESIAN_POINT('',(-500.,-274.688117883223,80.4951524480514));
#477=CARTESIAN_POINT('',(-500.,-269.421772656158,80.6783091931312));
#478=CARTESIAN_POINT('',(-500.,-266.789637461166,80.8064467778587));
#479=CARTESIAN_POINT('',(-500.,-261.529698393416,81.1291675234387));
#480=CARTESIAN_POINT('',(-500.,-258.901894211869,81.3237457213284));
#481=CARTESIAN_POINT('',(-500.,-253.652852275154,81.7720340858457));
#482=CARTESIAN_POINT('',(-500.,-251.031611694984,82.0257115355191));
#483=CARTESIAN_POINT('',(-500.,-245.756974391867,82.5887143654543));
#484=CARTESIAN_POINT('',(-500.,-243.103658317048,82.8987886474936));
#485=CARTESIAN_POINT('',(-500.,-237.803935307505,83.5637442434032));
#486=CARTESIAN_POINT('',(-500.,-235.157525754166,83.9186048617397));
#487=CARTESIAN_POINT('',(-500.,-229.869921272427,84.664957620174));
#488=CARTESIAN_POINT('',(-500.,-227.228726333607,85.0564496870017));
#489=CARTESIAN_POINT('',(-500.,-221.949853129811,85.8678692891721));
#490=CARTESIAN_POINT('',(-500.,-219.312176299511,86.2878060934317));
#491=CARTESIAN_POINT('',(-500.,-214.038641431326,87.147926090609));
#492=CARTESIAN_POINT('',(-500.,-211.40278522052,87.5881204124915));
#493=CARTESIAN_POINT('',(-500.,-206.13119797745,88.4805943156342));
#494=CARTESIAN_POINT('',(-500.,-203.495468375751,88.9328822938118));
#495=CARTESIAN_POINT('',(-500.,-199.131813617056,89.6847451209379));
#496=CARTESIAN_POINT('',(-500.,-197.403710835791,89.9832953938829));
#497=CARTESIAN_POINT('',(-500.,-193.94737729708,90.5796559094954));
#498=CARTESIAN_POINT('',(-500.,-192.219146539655,90.877466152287));
#499=CARTESIAN_POINT('',(-500.,-188.762162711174,91.4700768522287));
#500=CARTESIAN_POINT('',(-500.,-187.033409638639,91.7648773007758));
#501=CARTESIAN_POINT('',(-500.,-183.574338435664,92.3493275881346));
#502=CARTESIAN_POINT('',(-500.,-181.844019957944,92.6389753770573));
#503=CARTESIAN_POINT('',(-500.,-178.382142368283,93.2107603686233));
#504=CARTESIAN_POINT('',(-500.,-176.650583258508,93.4928975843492));
#505=CARTESIAN_POINT('',(-500.,-173.185901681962,94.0474339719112));
#506=CARTESIAN_POINT('',(-500.,-171.452779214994,94.3198331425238));
#507=CARTESIAN_POINT('',(-500.,-167.986171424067,94.8524478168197));
#508=CARTESIAN_POINT('',(-500.,-166.252687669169,95.1126735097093));
#509=CARTESIAN_POINT('',(-500.,-162.78363966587,95.618991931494));
#510=CARTESIAN_POINT('',(-500.,-161.048075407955,95.8650845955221));
#511=CARTESIAN_POINT('',(-500.,-158.443034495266,96.2219660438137));
#512=CARTESIAN_POINT('',(-500.,-157.574395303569,96.3388848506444));
#513=CARTESIAN_POINT('',(-500.,-155.836542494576,96.5683814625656));
#514=CARTESIAN_POINT('',(-500.,-154.967328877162,96.680959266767));
#515=CARTESIAN_POINT('',(-500.,-153.229456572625,96.9012648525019));
#516=CARTESIAN_POINT('',(-500.,-152.360798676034,97.0089988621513));
#517=CARTESIAN_POINT('',(-500.,-150.622840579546,97.2191676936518));
#518=CARTESIAN_POINT('',(-500.,-149.753540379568,97.3216025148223));
#519=CARTESIAN_POINT('',(-500.,-148.014285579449,97.5206069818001));
#520=CARTESIAN_POINT('',(-500.,-147.144330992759,97.6171767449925));
#521=CARTESIAN_POINT('',(-500.,-145.403730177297,97.8038806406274));
#522=CARTESIAN_POINT('',(-500.,-144.533083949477,97.8940147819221));
#523=CARTESIAN_POINT('',(-500.,-143.226606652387,98.0239702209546));
#524=CARTESIAN_POINT('',(-500.,-142.791035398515,98.0664138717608));
#525=CARTESIAN_POINT('',(-500.,-141.919719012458,98.1494769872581));
#526=CARTESIAN_POINT('',(-500.,-141.483973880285,98.1900964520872));
#527=CARTESIAN_POINT('',(-500.,-140.176490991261,98.3092415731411));
#528=CARTESIAN_POINT('',(-500.,-139.304504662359,98.3850540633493));
#529=CARTESIAN_POINT('',(-500.,-137.560483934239,98.5296111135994));
#530=CARTESIAN_POINT('',(-500.,-136.688449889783,98.5983599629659));
#531=CARTESIAN_POINT('',(-500.,-134.943872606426,98.7290377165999));
#532=CARTESIAN_POINT('',(-500.,-134.071329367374,98.7909666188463));
#533=CARTESIAN_POINT('',(-500.,-131.452952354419,98.9668199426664));
#534=CARTESIAN_POINT('',(-500.,-129.706442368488,99.0708051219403));
#535=CARTESIAN_POINT('',(-500.,-126.212103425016,99.2537484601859));
#536=CARTESIAN_POINT('',(-500.,-124.464274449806,99.3327062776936));
#537=CARTESIAN_POINT('',(-500.,-120.967568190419,99.4669931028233));
#538=CARTESIAN_POINT('',(-500.,-119.218690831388,99.52232015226));
#539=CARTESIAN_POINT('',(-500.,-115.720416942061,99.6106504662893));
#540=CARTESIAN_POINT('',(-500.,-113.971020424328,99.6436542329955));
#541=CARTESIAN_POINT('',(-500.,-110.471975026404,99.6885764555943));
#542=CARTESIAN_POINT('',(-500.,-108.722326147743,99.7004950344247));
#543=CARTESIAN_POINT('',(-500.,-104.380121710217,99.7053601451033));
#544=CARTESIAN_POINT('',(-500.,-101.787547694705,99.6864012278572));
#545=CARTESIAN_POINT('',(-500.,-96.6030198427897,99.6082571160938));
#546=CARTESIAN_POINT('',(-500.,-94.011066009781,99.5490717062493));
#547=CARTESIAN_POINT('',(-500.,-88.8238849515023,99.3934998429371));
#548=CARTESIAN_POINT('',(-500.,-86.2286596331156,99.2970504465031));
#549=CARTESIAN_POINT('',(-500.,-81.0397100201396,99.0698090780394));
#550=CARTESIAN_POINT('',(-500.,-78.44598573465,98.9390168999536));
#551=CARTESIAN_POINT('',(-500.,-73.2565176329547,98.6454152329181));
#552=CARTESIAN_POINT('',(-500.,-70.6607764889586,98.4825587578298));
#553=CARTESIAN_POINT('',(-500.,-65.471330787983,98.1272052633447));
#554=CARTESIAN_POINT('',(-500.,-62.8776262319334,97.9347082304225));
#555=CARTESIAN_POINT('',(-500.,-57.6899072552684,97.5218460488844));
#556=CARTESIAN_POINT('',(-500.,-55.0958949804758,97.3014540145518));
#557=CARTESIAN_POINT('',(-500.,-49.9102174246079,96.8346708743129));
#558=CARTESIAN_POINT('',(-500.,-47.3185521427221,96.5882797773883));
#559=CARTESIAN_POINT('',(-500.,-42.1369420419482,96.0709265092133));
#560=CARTESIAN_POINT('',(-500.,-39.5469979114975,95.7999574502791));
#561=CARTESIAN_POINT('',(-500.,-34.3696350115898,95.2348437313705));
#562=CARTESIAN_POINT('',(-500.,-31.7822162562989,94.9406989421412));
#563=CARTESIAN_POINT('',(-500.,-24.0265644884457,94.0256461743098));
#564=CARTESIAN_POINT('',(-500.,-18.8621809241,93.3718420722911));
#565=CARTESIAN_POINT('',(-500.,-10.0236385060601,92.1849948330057));
#566=CARTESIAN_POINT('',(-500.,-6.34687688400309,91.6710958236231));
#567=CARTESIAN_POINT('',(-500.,0.9984016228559,90.6082897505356));
#568=CARTESIAN_POINT('',(-500.,4.66692285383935,90.0594127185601));
#569=CARTESIAN_POINT('',(-500.,11.9974760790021,88.9317343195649));
#570=CARTESIAN_POINT('',(-500.,15.6595103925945,88.3529479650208));
#571=CARTESIAN_POINT('',(-500.,22.9790785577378,87.1718526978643));
#572=CARTESIAN_POINT('',(-500.,26.6366131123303,86.5695481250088));
#573=CARTESIAN_POINT('',(-500.,33.9494082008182,85.349330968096));
#574=CARTESIAN_POINT('',(-500.,37.6046684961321,84.7314169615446));
#575=CARTESIAN_POINT('',(-500.,43.0874316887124,83.8001305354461));
#576=CARTESIAN_POINT('',(-500.,44.9153028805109,83.4889135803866));
#577=CARTESIAN_POINT('',(-500.,48.5710407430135,82.8664529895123));
#578=CARTESIAN_POINT('',(-500.,50.3989074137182,82.555209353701));
#579=CARTESIAN_POINT('',(-500.,54.0630229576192,81.9328147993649));
#580=CARTESIAN_POINT('',(-500.,55.8992729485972,81.6216704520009));
#581=CARTESIAN_POINT('',(-500.,59.5723029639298,81.0025261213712));
#582=CARTESIAN_POINT('',(-500.,61.4090829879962,80.6945261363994));
#583=CARTESIAN_POINT('',(-500.,65.0837748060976,80.0834135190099));
#584=CARTESIAN_POINT('',(-500.,66.9216867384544,79.7803017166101));
#585=CARTESIAN_POINT('',(-500.,70.5986359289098,79.1809680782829));
#586=CARTESIAN_POINT('',(-500.,72.4376731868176,78.8847462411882));
#587=CARTESIAN_POINT('',(-500.,76.116990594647,78.3013434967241));
#588=CARTESIAN_POINT('',(-500.,77.9572705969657,78.0141616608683));
#589=CARTESIAN_POINT('',(-500.,81.6395608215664,77.4511220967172));
#590=CARTESIAN_POINT('',(-500.,83.4815710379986,77.1752643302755));
#591=CARTESIAN_POINT('',(-500.,87.1671740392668,76.6374722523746));
#592=CARTESIAN_POINT('',(-500.,89.0107663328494,76.3755345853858));
#593=CARTESIAN_POINT('',(-500.,92.700241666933,75.8682989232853));
#594=CARTESIAN_POINT('',(-500.,94.5461247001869,75.6230008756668));
#595=CARTESIAN_POINT('',(-500.,98.2401798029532,75.1521535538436));
#596=CARTESIAN_POINT('',(-500.,100.088351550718,74.9266017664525));
#597=CARTESIAN_POINT('',(-500.,103.787410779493,74.4986264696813));
#598=CARTESIAN_POINT('',(-500.,105.638298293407,74.2962032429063));
#599=CARTESIAN_POINT('',(-500.,109.343761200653,73.9182006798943));
#600=CARTESIAN_POINT('',(-500.,111.198337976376,73.7426348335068));
#601=CARTESIAN_POINT('',(-500.,114.910168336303,73.4227380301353));
#602=CARTESIAN_POINT('',(-500.,116.767421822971,73.2784059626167));
#603=CARTESIAN_POINT('',(-500.,119.35386501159,73.103898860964));
#604=CARTESIAN_POINT('',(-500.,120.081985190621,73.0576909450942));
#605=CARTESIAN_POINT('',(-500.,121.538592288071,72.9715284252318));
#606=CARTESIAN_POINT('',(-500.,122.267079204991,72.9315737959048));
#607=CARTESIAN_POINT('',(-500.,124.453080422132,72.8217638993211));
#608=CARTESIAN_POINT('',(-500.,125.91111913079,72.7619637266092));
#609=CARTESIAN_POINT('',(-500.,128.827666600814,72.6731598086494));
#610=CARTESIAN_POINT('',(-500.,130.28617503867,72.6441457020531));
#611=CARTESIAN_POINT('',(-500.,133.20274488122,72.6213325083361));
#612=CARTESIAN_POINT('',(-500.,134.660806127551,72.6275152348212));
#613=CARTESIAN_POINT('',(-500.,137.575609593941,72.6800344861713));
#614=CARTESIAN_POINT('',(-500.,139.03235211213,72.7263523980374));
#615=CARTESIAN_POINT('',(-500.,141.215749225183,72.8301111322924));
#616=CARTESIAN_POINT('',(-500.,141.943240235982,72.870409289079));
#617=CARTESIAN_POINT('',(-500.,143.397447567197,72.9632355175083));
#618=CARTESIAN_POINT('',(-500.,144.124163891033,73.0157635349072));
#619=CARTESIAN_POINT('',(-500.,145.569035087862,73.1331011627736));
#620=CARTESIAN_POINT('',(-500.,146.287200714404,73.197778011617));
#621=CARTESIAN_POINT('',(-500.,147.722273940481,73.3397853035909));
#622=CARTESIAN_POINT('',(-500.,148.439181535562,73.4171157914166));
#623=CARTESIAN_POINT('',(-500.,150.588434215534,73.6682913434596));
#624=CARTESIAN_POINT('',(-500.,152.018594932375,73.8612626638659));
#625=CARTESIAN_POINT('',(-500.,154.871617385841,74.2980883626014));
#626=CARTESIAN_POINT('',(-500.,156.294476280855,74.5419612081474));
#627=CARTESIAN_POINT('',(-500.,159.131013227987,75.0795910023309));
#628=CARTESIAN_POINT('',(-500.,160.54468949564,75.373357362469));
#629=CARTESIAN_POINT('',(-500.,163.361097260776,76.0088191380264));
#630=CARTESIAN_POINT('',(-500.,164.763829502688,76.3505112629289));
#631=CARTESIAN_POINT('',(-500.,167.556803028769,77.0788905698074));
#632=CARTESIAN_POINT('',(-500.,168.947050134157,77.4655554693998));
#633=CARTESIAN_POINT('',(-500.,171.355757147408,78.1745754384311));
#634=CARTESIAN_POINT('',(-500.,172.376996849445,78.487549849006));
#635=CARTESIAN_POINT('',(-500.,174.412381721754,79.1344044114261));
#636=CARTESIAN_POINT('',(-500.,175.426529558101,79.4682761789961));
#637=CARTESIAN_POINT('',(-500.,177.448079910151,80.1550684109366));
#638=CARTESIAN_POINT('',(-500.,178.455483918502,80.5079844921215));
#639=CARTESIAN_POINT('',(-500.,180.46396938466,81.2308363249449));
#640=CARTESIAN_POINT('',(-500.,181.465051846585,81.6007692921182));
#641=CARTESIAN_POINT('',(-500.,183.468735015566,82.3582642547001));
#642=CARTESIAN_POINT('',(-500.,184.4712949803,82.7459337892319));
#643=CARTESIAN_POINT('',(-500.,186.471414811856,83.534149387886));
#644=CARTESIAN_POINT('',(-500.,187.46897430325,83.9346964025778));
#645=CARTESIAN_POINT('',(-500.,189.460050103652,84.7464013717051));
#646=CARTESIAN_POINT('',(-500.,190.453565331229,85.157561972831));
#647=CARTESIAN_POINT('',(-500.,192.437527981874,85.9881880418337));
#648=CARTESIAN_POINT('',(-500.,193.427974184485,86.4076564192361));
#649=CARTESIAN_POINT('',(-500.,196.586251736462,87.7561531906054));
#650=CARTESIAN_POINT('',(-500.,198.749358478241,88.6962057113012));
#651=CARTESIAN_POINT('',(-500.,201.993127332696,90.1090881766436));
#652=CARTESIAN_POINT('',(-500.,203.074389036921,90.580583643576));
#653=CARTESIAN_POINT('',(-500.,205.237779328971,91.5215801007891));
#654=CARTESIAN_POINT('',(-500.,206.319907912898,91.9910810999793));
#655=CARTESIAN_POINT('',(-500.,208.485849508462,92.9251423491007));
#656=CARTESIAN_POINT('',(-500.,209.569661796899,93.3897042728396));
#657=CARTESIAN_POINT('',(-500.,211.740437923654,94.3114222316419));
#658=CARTESIAN_POINT('',(-500.,212.827401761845,94.7685782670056));
#659=CARTESIAN_POINT('',(-500.,215.004661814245,95.6726898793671));
#660=CARTESIAN_POINT('',(-500.,216.094955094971,96.1196525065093));
#661=CARTESIAN_POINT('',(-500.,218.28045248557,97.0014272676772));
#662=CARTESIAN_POINT('',(-500.,219.375656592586,97.4362394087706));
#663=CARTESIAN_POINT('',(-500.,221.57094715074,98.2913583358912));
#664=CARTESIAN_POINT('',(-500.,222.671030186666,98.7116738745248));
#665=CARTESIAN_POINT('',(-500.,224.8772246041,99.5361992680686));
#666=CARTESIAN_POINT('',(-500.,225.983335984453,99.9404091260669));
#667=CARTESIAN_POINT('',(-500.,228.201886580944,100.73105609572));
#668=CARTESIAN_POINT('',(-500.,229.314325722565,101.117493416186));
#669=CARTESIAN_POINT('',(-500.,231.545697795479,101.871163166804));
#670=CARTESIAN_POINT('',(-500.,232.664630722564,102.238395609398));
#671=CARTESIAN_POINT('',(-500.,234.896625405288,102.948511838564));
#672=CARTESIAN_POINT('',(-500.,236.009615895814,103.291619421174));
#673=CARTESIAN_POINT('',(-500.,238.241834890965,103.956920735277));
#674=CARTESIAN_POINT('',(-500.,239.361063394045,104.27911447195));
#675=CARTESIAN_POINT('',(-500.,241.606825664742,104.902211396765));
#676=CARTESIAN_POINT('',(-500.,242.733366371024,105.203089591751));
#677=CARTESIAN_POINT('',(-500.,244.99215435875,105.782613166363));
#678=CARTESIAN_POINT('',(-500.,246.124401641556,106.061258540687));
#679=CARTESIAN_POINT('',(-500.,248.395052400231,106.596173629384));
#680=CARTESIAN_POINT('',(-500.,249.533459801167,106.852426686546));
#681=CARTESIAN_POINT('',(-500.,251.815160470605,107.342164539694));
#682=CARTESIAN_POINT('',(-500.,252.958453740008,107.575649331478));
#683=CARTESIAN_POINT('',(-500.,255.249961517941,108.019946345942));
#684=CARTESIAN_POINT('',(-500.,256.398177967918,108.230748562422));
#685=CARTESIAN_POINT('',(-500.,258.698545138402,108.629710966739));
#686=CARTESIAN_POINT('',(-500.,259.850695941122,108.817870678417));
#687=CARTESIAN_POINT('',(-500.,263.31250762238,109.348780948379));
#688=CARTESIAN_POINT('',(-500.,265.627404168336,109.657938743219));
#689=CARTESIAN_POINT('',(-500.,270.266041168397,110.18979375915));
#690=CARTESIAN_POINT('',(-500.,272.5897776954,110.41252566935));
#691=CARTESIAN_POINT('',(-500.,277.251892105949,110.77679823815));
#692=CARTESIAN_POINT('',(-500.,279.590292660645,110.918046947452));
#693=CARTESIAN_POINT('',(-500.,284.269581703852,111.123160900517));
#694=CARTESIAN_POINT('',(-500.,286.610469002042,111.187053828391));
#695=CARTESIAN_POINT('',(-500.,291.293044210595,111.242875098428));
#696=CARTESIAN_POINT('',(-500.,293.63473211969,111.234803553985));
#697=CARTESIAN_POINT('',(-500.,298.317217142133,111.151994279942));
#698=CARTESIAN_POINT('',(-500.,300.658014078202,111.07724693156));
#699=CARTESIAN_POINT('',(-500.,305.3370271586,110.866174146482));
#700=CARTESIAN_POINT('',(-500.,307.675243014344,110.729842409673));
#701=CARTESIAN_POINT('',(-500.,312.347398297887,110.40042915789));
#702=CARTESIAN_POINT('',(-500.,314.681338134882,110.20735339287));
#703=CARTESIAN_POINT('',(-500.,319.369380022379,109.766544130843));
#704=CARTESIAN_POINT('',(-500.,321.72342850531,109.518244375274));
#705=CARTESIAN_POINT('',(-500.,326.425129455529,108.972508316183));
#706=CARTESIAN_POINT('',(-500.,328.772783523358,108.675085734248));
#707=CARTESIAN_POINT('',(-500.,333.461584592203,108.034921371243));
#708=CARTESIAN_POINT('',(-500.,335.802732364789,107.692185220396));
#709=CARTESIAN_POINT('',(-500.,340.478352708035,106.964843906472));
#710=CARTESIAN_POINT('',(-500.,342.812825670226,106.580241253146));
#711=CARTESIAN_POINT('',(-500.,347.474872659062,105.772292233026));
#712=CARTESIAN_POINT('',(-500.,349.802447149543,105.348948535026));
#713=CARTESIAN_POINT('',(-500.,354.450446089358,104.466353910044));
#714=CARTESIAN_POINT('',(-500.,356.770871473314,104.007107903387));
#715=CARTESIAN_POINT('',(-500.,359.977573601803,103.348368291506));
#716=CARTESIAN_POINT('',(-500.,360.866801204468,103.163127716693));
#717=CARTESIAN_POINT('',(-500.,362.644186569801,102.78785624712));
#718=CARTESIAN_POINT('',(-500.,363.532344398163,102.597825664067));
#719=CARTESIAN_POINT('',(-500.,365.307618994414,102.213096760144));
#720=CARTESIAN_POINT('',(-500.,366.194735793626,102.018398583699));
#721=CARTESIAN_POINT('',(-500.,367.962657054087,101.625628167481));
#722=CARTESIAN_POINT('',(-500.,368.843467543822,101.42758306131));
#723=CARTESIAN_POINT('',(-500.,370.604118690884,101.027104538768));
#724=CARTESIAN_POINT('',(-500.,371.483959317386,100.824670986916));
#725=CARTESIAN_POINT('',(-500.,373.242698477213,100.415519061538));
#726=CARTESIAN_POINT('',(-500.,374.121596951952,100.208800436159));
#727=CARTESIAN_POINT('',(-500.,375.,100.));
#728=B_SPLINE_CURVE_WITH_KNOTS('',3,(#446,#447,#448,#449,#450,#451,#452,#453,#454,#455,#456,
#457,#458,#459,#460,#461,#462,#463,#464,#465,#466,#467,#468,#469,#470,#471,#472,#473,#474,#475,
#476,#477,#478,#479,#480,#481,#482,#483,#484,#485,#486,#487,#488,#489,#490,#491,#492,#493,#494,
#495,#496,#497,#498,#499,#500,#501,#502,#503,#504,#505,#506,#507,#508,#509,#510,#511,#512,#513,
#514,#515,#516,#517,#518,#519,#520,#521,#522,#523,#524,#525,#526,#527,#528,#529,#530,#531,#532,
#533,#534,#535,#536,#537,#538,#539,#540,#541,#542,#543,#544,#545,#546,#547,#548,#549,#550,#551,
#552,#553,#554,#555,#556,#557,#558,#559,#560,#561,#562,#563,#564,#565,#566,#567,#568,#569,#570,
#571,#572,#573,#574,#575,#576,#577,#578,#579,#580,#581,#582,#583,#584,#585,#586,#587,#588,#589,
#590,#591,#592,#593,#594,#595,#596,#597,#598,#599,#600,#601,#602,#603,#604,#605,#606,#607,#608,
#609,#610,#611,#612,#613,#614,#615,#616,#617,#618,#619,#620,#621,#622,#623,#624,#625,#626,#627,
#628,#629,#630,#631,#632,#633,#634,#635,#636,#637,#638,#639,#640,#641,#642,#643,#644,#645,#646,
#647,#648,#649,#650,#651,#652,#653,#654,#655,#656,#657,#658,#659,#660,#661,#662,#663,#664,#665,
#666,#667,#668,#669,#670,#671,#672,#673,#674,#675,#676,#677,#678,#679,#680,#681,#682,#683,#684,
#685,#686,#687,#688,#689,#690,#691,#692,#693,#694,#695,#696,#697,#698,#699,#700,#701,#702,#703,
#704,#705,#706,#707,#708,#709,#710,#711,#712,#713,#714,#715,#716,#717,#718,#719,#720,#721,#722,
#723,#724,#725,#726,#727),.UNSPECIFIED.,.F.,.F.,(4,2,2,2,2,2,2,2,2,2,2,2,2,2,2,2,2,2,2,2,2,2,2,
2,2,2,2,2,2,2,2,2,2,2,2,2,2,2,2,2,2,2,2,2,2,2,2,2,2,2,2,2,2,2,2,2,2,2,2,2,2,2,2,2,2,2,2,2,2,2,2,
2,2,2,2,2,2,2,2,2,2,2,2,2,2,2,2,2,2,2,2,2,2,2,2,2,2,2,2,2,2,2,2,2,2,2,2,2,2,2,2,2,2,2,2,2,2,2,2,
2,2,2,2,2,2,2,2,2,2,2,2,2,2,2,2,2,2,2,2,2,4),(0.,6.96910036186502,13.9409495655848,
20.9138442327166,27.8867202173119,34.8590865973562,41.8309235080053,48.5220289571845,
55.2120968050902,61.9013314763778,68.5899836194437,75.2781569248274,81.9656085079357,
89.8651834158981,97.7662215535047,105.66947122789,113.57430162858,121.47854168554,
129.378416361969,137.392077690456,145.402049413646,153.412005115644,161.424583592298,
169.44161778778,177.464370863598,182.725478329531,187.986584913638,193.247706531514,
198.510876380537,203.774037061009,209.037198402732,214.29587263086,219.55457099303,
222.183979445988,224.813388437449,227.439313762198,230.065239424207,232.691112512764,
235.316981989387,236.629881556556,237.942781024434,240.568576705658,243.192768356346,
245.816960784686,251.065559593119,256.314230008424,261.563335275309,266.81232247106,
272.061279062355,279.838845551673,287.616453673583,295.407256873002,303.198106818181,
311.000459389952,318.802815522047,326.612749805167,334.422681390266,342.234808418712,
350.046979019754,365.663014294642,376.800357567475,387.92826402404,399.050638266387,
410.170969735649,421.292318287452,426.854847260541,432.417375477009,438.004647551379,
443.591916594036,449.180124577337,454.76833161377,460.355962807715,465.9435751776,
471.52983445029,477.116076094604,482.701605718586,488.287203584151,493.875597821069,
499.463793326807,501.652525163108,503.841248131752,508.21874234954,512.59476281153,
516.968522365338,521.340254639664,523.525988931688,525.711713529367,527.874812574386,
530.037919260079,534.36628121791,538.696216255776,543.026968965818,547.357424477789,
551.685743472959,554.889882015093,558.092743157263,561.294870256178,564.496475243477,
567.72107649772,570.945916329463,574.171568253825,577.398370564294,584.473913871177,
588.012693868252,591.551458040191,595.088982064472,598.626505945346,602.161504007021,
605.696500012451,609.229322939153,612.762145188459,616.294925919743,619.8277043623,
623.321536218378,626.815367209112,630.313229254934,633.811092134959,637.311535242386,
640.811978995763,644.313960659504,647.816015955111,654.820503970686,661.822177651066,
668.848784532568,675.872875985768,682.89695637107,689.922050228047,696.947862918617,
703.972963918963,711.073723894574,718.172503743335,725.270402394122,732.367875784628,
739.464860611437,746.560874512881,749.285816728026,752.010582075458,754.735263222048,
757.44365353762,760.1521275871,762.860761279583),.UNSPECIFIED.);
#729=CARTESIAN_POINT('',(-500.,-375.,100.));
#730=VERTEX_POINT('',#729);
#731=CARTESIAN_POINT('',(-500.,375.,100.));
#732=VERTEX_POINT('',#731);
#733=EDGE_CURVE('E11',#730,#732,#728,.T.);
#734=CARTESIAN_POINT('',(-750.,-375.,100.));
#735=CARTESIAN_POINT('',(-644.685568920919,-375.,100.));
#736=CARTESIAN_POINT('',(-536.684515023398,-375.,100.));
#737=CARTESIAN_POINT('',(-355.235514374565,-375.,100.));
#738=CARTESIAN_POINT('',(-175.903454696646,-375.,100.));
#739=CARTESIAN_POINT('',(47.4554331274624,-375.,100.));
#740=CARTESIAN_POINT('',(285.091607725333,-375.,100.));
#741=CARTESIAN_POINT('',(500.445116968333,-375.,100.));
#742=CARTESIAN_POINT('',(669.085175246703,-375.,100.));
#743=CARTESIAN_POINT('',(750.,-375.,100.));
#744=B_SPLINE_CURVE_WITH_KNOTS('',3,(#734,#735,#736,#737,#738,#739,#740,#741,#742,#743),
.UNSPECIFIED.,.F.,.F.,(4,1,1,1,1,1,1,4),(0.,0.210628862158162,0.216002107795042,
0.362898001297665,0.569292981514,0.66271988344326,0.838170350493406,1.),.UNSPECIFIED.);
#745=EDGE_CURVE('E97',#730,#306,#744,.T.);
#746=CARTESIAN_POINT('',(750.,375.,100.));
#747=CARTESIAN_POINT('',(669.085175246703,375.,100.));
#748=CARTESIAN_POINT('',(500.445116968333,375.,100.));
#749=CARTESIAN_POINT('',(285.091607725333,375.,100.));
#750=CARTESIAN_POINT('',(47.4554331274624,375.,100.));
#751=CARTESIAN_POINT('',(-175.903454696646,375.,100.));
#752=CARTESIAN_POINT('',(-355.235514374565,375.,100.));
#753=CARTESIAN_POINT('',(-536.684515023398,375.,100.));
#754=CARTESIAN_POINT('',(-644.685568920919,375.,100.));
#755=CARTESIAN_POINT('',(-750.,375.,100.));
#756=B_SPLINE_CURVE_WITH_KNOTS('',3,(#746,#747,#748,#749,#750,#751,#752,#753,#754,#755),
.UNSPECIFIED.,.F.,.F.,(4,1,1,1,1,1,1,4),(0.,0.161829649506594,0.33728011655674,0.430707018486,
0.637101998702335,0.783997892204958,0.789371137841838,1.),.UNSPECIFIED.);
#757=EDGE_CURVE('E94',#304,#732,#756,.T.);
#758=ORIENTED_EDGE('',*,*,#733,.F.);
#759=ORIENTED_EDGE('',*,*,#745,.T.);
#760=ORIENTED_EDGE('',*,*,#307,.F.);
#761=ORIENTED_EDGE('',*,*,#757,.T.);
#762=EDGE_LOOP('',(#758,#759,#760,#761));
#763=FACE_BOUND('',#762,.T.);
#764=ADVANCED_FACE('F110',(#763),#445,.F.);
#765=CARTESIAN_POINT('',(-750.,375.,253.111113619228));
#766=DIRECTION('',(0.,-1.,0.));
#767=DIRECTION('',(0.,0.,-1.));
#768=AXIS2_PLACEMENT_3D('',#765,#766,#767);
#769=PLANE('',#768);
#770=DIRECTION('',(0.,0.,-1.));
#771=VECTOR('',#770,1.);
#772=CARTESIAN_POINT('',(-500.,375.,253.120113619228));
#773=LINE('',#772,#771);
#774=EDGE_CURVE('E154',#732,#352,#773,.T.);
#775=ORIENTED_EDGE('',*,*,#774,.F.);
#776=ORIENTED_EDGE('',*,*,#757,.F.);
#777=ORIENTED_EDGE('',*,*,#329,.T.);
#778=ORIENTED_EDGE('',*,*,#359,.T.);
#779=EDGE_LOOP('',(#775,#776,#777,#778));
#780=FACE_BOUND('',#779,.T.);
#781=ADVANCED_FACE('F121',(#780),#769,.F.);
#782=CARTESIAN_POINT('',(-750.,-375.,253.111113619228));
#783=DIRECTION('',(0.,1.,0.));
#784=DIRECTION('',(0.,0.,1.));
#785=AXIS2_PLACEMENT_3D('',#782,#783,#784);
#786=PLANE('',#785);
#787=DIRECTION('',(0.,0.,-1.));
#788=VECTOR('',#787,1.);
#789=CARTESIAN_POINT('',(-500.,-375.,253.120113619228));
#790=LINE('',#789,#788);
#791=EDGE_CURVE('E56',#730,#344,#790,.T.);
#792=ORIENTED_EDGE('',*,*,#791,.T.);
#793=ORIENTED_EDGE('',*,*,#345,.T.);
#794=ORIENTED_EDGE('',*,*,#315,.F.);
#795=ORIENTED_EDGE('',*,*,#745,.F.);
#796=EDGE_LOOP('',(#792,#793,#794,#795));
#797=FACE_BOUND('',#796,.T.);
#798=ADVANCED_FACE('F37',(#797),#786,.F.);
#799=CARTESIAN_POINT('',(-500.,375.,253.120113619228));
#800=DIRECTION('',(-1.,0.,0.));
#801=DIRECTION('',(0.,-1.,0.));
#802=AXIS2_PLACEMENT_3D('',#799,#800,#801);
#803=PLANE('',#802);
#804=ORIENTED_EDGE('',*,*,#733,.T.);
#805=ORIENTED_EDGE('',*,*,#774,.T.);
#806=ORIENTED_EDGE('',*,*,#353,.F.);
#807=ORIENTED_EDGE('',*,*,#791,.F.);
#808=EDGE_LOOP('',(#804,#805,#806,#807));
#809=FACE_BOUND('',#808,.T.);
#810=ADVANCED_FACE('F145',(#809),#803,.T.);
#811=CLOSED_SHELL('',(#333,#364,#764,#781,#798,#810));
#812=MANIFOLD_SOLID_BREP('B2',#811);
#813=ADVANCED_BREP_SHAPE_REPRESENTATION('',(#18,#812),#14);
#814=SHAPE_DEFINITION_REPRESENTATION(#9,#813);
ENDSEC;
END-ISO-10303-21;
